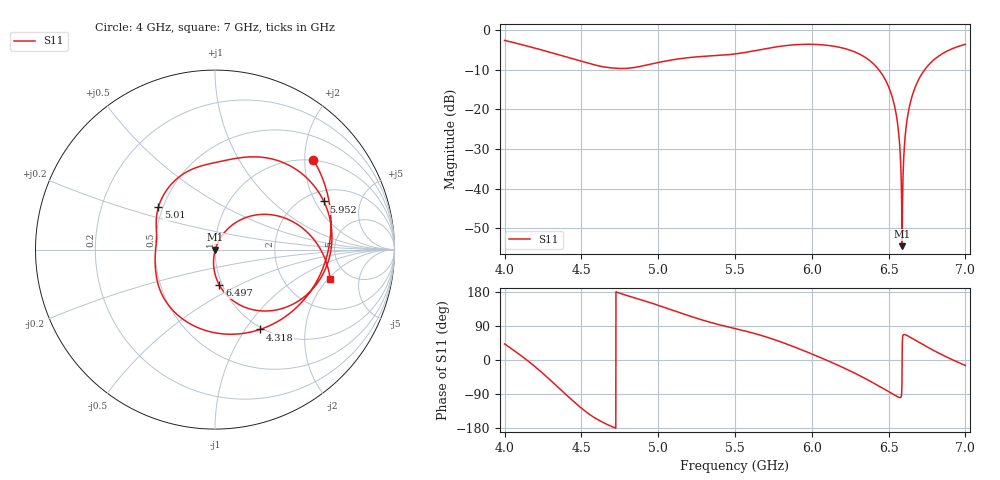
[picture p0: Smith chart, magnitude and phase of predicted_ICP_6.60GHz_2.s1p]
! ICP-predicted S11, target max centred GHz at -10 dB. Complex ensemble mean (passive and causal);
! its |S11| can differ slightly from the dB-domain mean reported in designs.csv.
!  Air_gap = 2.23mm
!  W_Patch = 14.26mm
!  L_Patch = 18.09mm
!  Sx = 1.21mm
!  Sy = 3.8mm
!  W_Patch1 = 11.14mm
!  WS = 1.41mm
!  Curve_Amp1 = 3.11mm
!  Extra = 7.62mm
# GHz S MA R 50
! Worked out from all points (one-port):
!   3001 points, 4 GHz to 7 GHz, reference 50 ohm
!   lowest |S11| = -54.6 dB at 6.588 GHz (marker M1), VSWR 1.00, Z = 50.2 - j0.00651 ohm
!   |S11| at or under -10 dB: 6.436 GHz to 6.735 GHz (298.5 MHz wide, 4.53 % of centre)
!   S11 on the Smith chart (normalised r, x): 4 GHz: 0.99, +2.20; 4.318 GHz: 0.97, -1.17; 5.01 GHz: 0.47, +0.27; 5.952 GHz: 2.47, +2.37; 6.497 GHz: 0.97, -0.40; 7 GHz: 3.60, -2.13
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4  0.7418 42.4
4.156  0.6236 -3.7
4.318  0.5108 -60.6
4.375  0.4758 -82.0
4.531  0.392 -137.0
4.75  0.3285 176.2
5.01  0.3945 142.9
5.125  0.4317 127.0
5.5  0.5014 83.0
5.72  0.5935 58.7
5.875  0.6517 36.2
5.952  0.6632 23.9
6.103  0.6433 -1.7
6.25  0.5584 -28.9
6.376  0.4142 -55.0
6.497  0.1992 -83.0
6.529  0.1314 -90.5
6.552  0.08072 -95.8
6.566  0.04936 -98.4
6.578  0.0223 -98.8
6.588  0.001868 -2.0
6.598  0.02324 67.0
6.61  0.05044 66.5
6.625  0.08435 63.6
6.671  0.186 53.0
6.745  0.3353 35.9
6.881  0.5448 7.3
7  0.6631 -14.5
